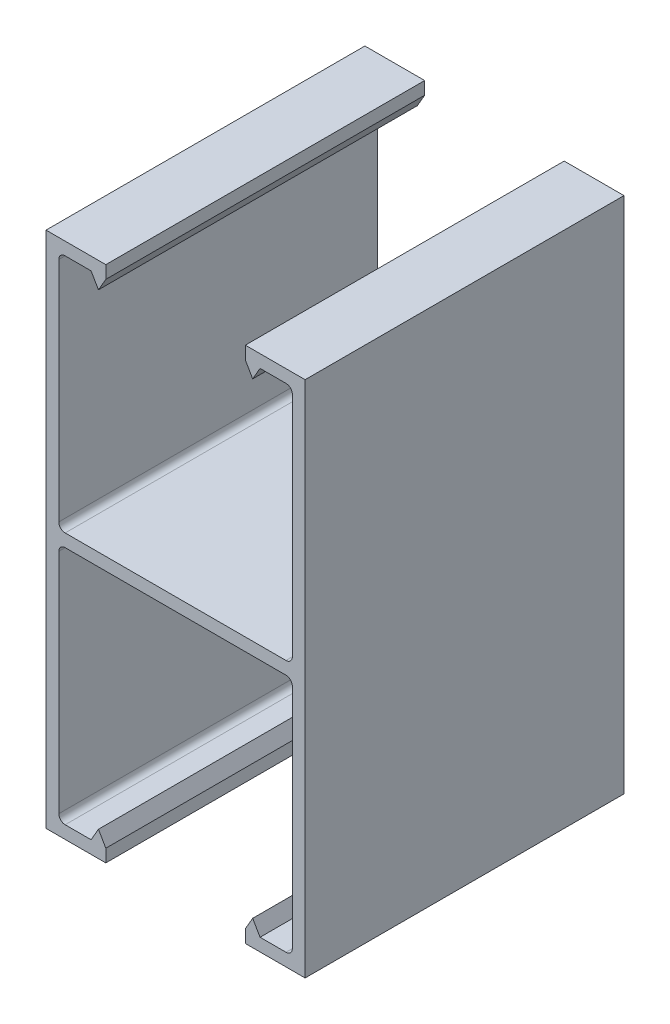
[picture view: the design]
ISO-10303-21;
HEADER;
FILE_DESCRIPTION(('STEP AP214'),'2;1');
FILE_NAME('part.step','',(''),(''),'','','');
FILE_SCHEMA(('AUTOMOTIVE_DESIGN { 1 0 10303 214 1 1 1 1 }'));
ENDSEC;
DATA;
#1=APPLICATION_CONTEXT('core data for automotive mechanical design processes');
#2=APPLICATION_PROTOCOL_DEFINITION('international standard','automotive_design',2000,#1);
#3=PRODUCT_CONTEXT('',#1,'mechanical');
#4=PRODUCT('Part','Part','',(#3));
#5=PRODUCT_RELATED_PRODUCT_CATEGORY('part','',(#4));
#6=PRODUCT_DEFINITION_FORMATION('','',#4);
#7=PRODUCT_DEFINITION_CONTEXT('part definition',#1,'design');
#8=PRODUCT_DEFINITION('design','',#6,#7);
#9=PRODUCT_DEFINITION_SHAPE('','',#8);
#10=(LENGTH_UNIT() NAMED_UNIT(*) SI_UNIT(.MILLI.,.METRE.));
#11=(NAMED_UNIT(*) PLANE_ANGLE_UNIT() SI_UNIT($,.RADIAN.));
#12=(NAMED_UNIT(*) SI_UNIT($,.STERADIAN.) SOLID_ANGLE_UNIT());
#13=UNCERTAINTY_MEASURE_WITH_UNIT(LENGTH_MEASURE(1.E-05),#10,'distance_accuracy_value','');
#14=(GEOMETRIC_REPRESENTATION_CONTEXT(3) GLOBAL_UNCERTAINTY_ASSIGNED_CONTEXT((#13)) GLOBAL_UNIT_ASSIGNED_CONTEXT((#10,
#11,#12)) REPRESENTATION_CONTEXT('',''));
#15=CARTESIAN_POINT('',(0.,0.,0.));
#16=DIRECTION('',(0.,0.,1.));
#17=DIRECTION('',(1.,0.,0.));
#18=AXIS2_PLACEMENT_3D('',#15,#16,#17);
#19=CARTESIAN_POINT('',(-8.79475,1.016,12.7));
#20=DIRECTION('',(0.,0.,-1.));
#21=DIRECTION('',(-1.,0.,0.));
#22=AXIS2_PLACEMENT_3D('',#19,#20,#21);
#23=CYLINDRICAL_SURFACE('',#22,0.508);
#24=CARTESIAN_POINT('',(-8.79475,1.016,-12.7));
#25=DIRECTION('',(0.,0.,-1.));
#26=DIRECTION('',(1.,0.,0.));
#27=AXIS2_PLACEMENT_3D('',#24,#25,#26);
#28=CIRCLE('',#27,0.508);
#29=CARTESIAN_POINT('',(-8.79475,0.508000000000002,-12.7));
#30=VERTEX_POINT('',#29);
#31=CARTESIAN_POINT('',(-9.30274999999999,1.016,-12.7));
#32=VERTEX_POINT('',#31);
#33=EDGE_CURVE('E296',#30,#32,#28,.T.);
#34=ORIENTED_EDGE('',*,*,#33,.T.);
#35=DIRECTION('',(0.,0.,-1.));
#36=VECTOR('',#35,1.);
#37=CARTESIAN_POINT('',(-9.30274999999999,1.016,12.7));
#38=LINE('',#37,#36);
#39=CARTESIAN_POINT('',(-9.30274999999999,1.016,12.7));
#40=VERTEX_POINT('',#39);
#41=EDGE_CURVE('E11',#40,#32,#38,.T.);
#42=ORIENTED_EDGE('',*,*,#41,.F.);
#43=CARTESIAN_POINT('',(-8.79475,1.016,12.7));
#44=DIRECTION('',(0.,0.,-1.));
#45=DIRECTION('',(1.,0.,0.));
#46=AXIS2_PLACEMENT_3D('',#43,#44,#45);
#47=CIRCLE('',#46,0.508);
#48=CARTESIAN_POINT('',(-8.79475,0.508000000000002,12.7));
#49=VERTEX_POINT('',#48);
#50=EDGE_CURVE('E366',#49,#40,#47,.T.);
#51=ORIENTED_EDGE('',*,*,#50,.F.);
#52=DIRECTION('',(0.,0.,-1.));
#53=VECTOR('',#52,1.);
#54=CARTESIAN_POINT('',(-8.79475,0.508000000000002,12.7));
#55=LINE('',#54,#53);
#56=EDGE_CURVE('E292',#49,#30,#55,.T.);
#57=ORIENTED_EDGE('',*,*,#56,.T.);
#58=EDGE_LOOP('',(#34,#42,#51,#57));
#59=FACE_BOUND('',#58,.T.);
#60=ADVANCED_FACE('F32',(#59),#23,.F.);
#61=CARTESIAN_POINT('',(-9.30275,19.1135,12.7));
#62=DIRECTION('',(-1.,0.,0.));
#63=DIRECTION('',(0.,-1.,0.));
#64=AXIS2_PLACEMENT_3D('',#61,#62,#63);
#65=PLANE('',#64);
#66=DIRECTION('',(0.,1.,0.));
#67=VECTOR('',#66,1.);
#68=CARTESIAN_POINT('',(-9.30275,19.1135,-12.7));
#69=LINE('',#68,#67);
#70=CARTESIAN_POINT('',(-9.30275,19.1135,-12.7));
#71=VERTEX_POINT('',#70);
#72=EDGE_CURVE('E299',#32,#71,#69,.T.);
#73=ORIENTED_EDGE('',*,*,#72,.T.);
#74=DIRECTION('',(0.,0.,-1.));
#75=VECTOR('',#74,1.);
#76=CARTESIAN_POINT('',(-9.30275,19.1135,12.7));
#77=LINE('',#76,#75);
#78=CARTESIAN_POINT('',(-9.30275,19.1135,12.7));
#79=VERTEX_POINT('',#78);
#80=EDGE_CURVE('E40',#79,#71,#77,.T.);
#81=ORIENTED_EDGE('',*,*,#80,.F.);
#82=DIRECTION('',(0.,1.,0.));
#83=VECTOR('',#82,1.);
#84=CARTESIAN_POINT('',(-9.30275,19.1135,12.7));
#85=LINE('',#84,#83);
#86=EDGE_CURVE('E175',#40,#79,#85,.T.);
#87=ORIENTED_EDGE('',*,*,#86,.F.);
#88=ORIENTED_EDGE('',*,*,#41,.T.);
#89=EDGE_LOOP('',(#73,#81,#87,#88));
#90=FACE_BOUND('',#89,.T.);
#91=ADVANCED_FACE('F564',(#90),#65,.F.);
#92=CARTESIAN_POINT('',(-8.79475,19.1135,12.7));
#93=DIRECTION('',(0.,0.,-1.));
#94=DIRECTION('',(-1.,0.,0.));
#95=AXIS2_PLACEMENT_3D('',#92,#93,#94);
#96=CYLINDRICAL_SURFACE('',#95,0.508000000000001);
#97=CARTESIAN_POINT('',(-8.79475,19.1135,-12.7));
#98=DIRECTION('',(0.,0.,-1.));
#99=DIRECTION('',(1.,0.,0.));
#100=AXIS2_PLACEMENT_3D('',#97,#98,#99);
#101=CIRCLE('',#100,0.508000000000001);
#102=CARTESIAN_POINT('',(-8.79475,19.6215,-12.7));
#103=VERTEX_POINT('',#102);
#104=EDGE_CURVE('E301',#71,#103,#101,.T.);
#105=ORIENTED_EDGE('',*,*,#104,.T.);
#106=DIRECTION('',(0.,0.,-1.));
#107=VECTOR('',#106,1.);
#108=CARTESIAN_POINT('',(-8.79475,19.6215,12.7));
#109=LINE('',#108,#107);
#110=CARTESIAN_POINT('',(-8.79475,19.6215,12.7));
#111=VERTEX_POINT('',#110);
#112=EDGE_CURVE('E457',#111,#103,#109,.T.);
#113=ORIENTED_EDGE('',*,*,#112,.F.);
#114=CARTESIAN_POINT('',(-8.79475,19.1135,12.7));
#115=DIRECTION('',(0.,0.,-1.));
#116=DIRECTION('',(1.,0.,0.));
#117=AXIS2_PLACEMENT_3D('',#114,#115,#116);
#118=CIRCLE('',#117,0.508000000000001);
#119=EDGE_CURVE('E465',#79,#111,#118,.T.);
#120=ORIENTED_EDGE('',*,*,#119,.F.);
#121=ORIENTED_EDGE('',*,*,#80,.T.);
#122=EDGE_LOOP('',(#105,#113,#120,#121));
#123=FACE_BOUND('',#122,.T.);
#124=ADVANCED_FACE('F463',(#123),#96,.F.);
#125=CARTESIAN_POINT('',(-6.72942574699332,19.6215,12.7));
#126=DIRECTION('',(0.,1.,0.));
#127=DIRECTION('',(-1.,0.,0.));
#128=AXIS2_PLACEMENT_3D('',#125,#126,#127);
#129=PLANE('',#128);
#130=DIRECTION('',(1.,0.,0.));
#131=VECTOR('',#130,1.);
#132=CARTESIAN_POINT('',(-6.72942574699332,19.6215,-12.7));
#133=LINE('',#132,#131);
#134=CARTESIAN_POINT('',(-6.72942574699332,19.6215,-12.7));
#135=VERTEX_POINT('',#134);
#136=EDGE_CURVE('E303',#103,#135,#133,.T.);
#137=ORIENTED_EDGE('',*,*,#136,.T.);
#138=DIRECTION('',(0.,0.,-1.));
#139=VECTOR('',#138,1.);
#140=CARTESIAN_POINT('',(-6.72942574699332,19.6215,12.7));
#141=LINE('',#140,#139);
#142=CARTESIAN_POINT('',(-6.72942574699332,19.6215,12.7));
#143=VERTEX_POINT('',#142);
#144=EDGE_CURVE('E454',#143,#135,#141,.T.);
#145=ORIENTED_EDGE('',*,*,#144,.F.);
#146=DIRECTION('',(1.,0.,0.));
#147=VECTOR('',#146,1.);
#148=CARTESIAN_POINT('',(-6.72942574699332,19.6215,12.7));
#149=LINE('',#148,#147);
#150=EDGE_CURVE('E483',#111,#143,#149,.T.);
#151=ORIENTED_EDGE('',*,*,#150,.F.);
#152=ORIENTED_EDGE('',*,*,#112,.T.);
#153=EDGE_LOOP('',(#137,#145,#151,#152));
#154=FACE_BOUND('',#153,.T.);
#155=ADVANCED_FACE('F474',(#154),#129,.F.);
#156=CARTESIAN_POINT('',(-6.72942574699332,19.6215,12.7));
#157=DIRECTION('',(0.866025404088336,0.499999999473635,0.));
#158=DIRECTION('',(-0.499999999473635,0.866025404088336,0.));
#159=AXIS2_PLACEMENT_3D('',#156,#157,#158);
#160=PLANE('',#159);
#161=DIRECTION('',(0.499999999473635,-0.866025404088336,0.));
#162=VECTOR('',#161,1.);
#163=CARTESIAN_POINT('',(-6.72942574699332,19.6215,-12.7));
#164=LINE('',#163,#162);
#165=CARTESIAN_POINT('',(-6.14283787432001,18.6055,-12.7));
#166=VERTEX_POINT('',#165);
#167=EDGE_CURVE('E305',#135,#166,#164,.T.);
#168=ORIENTED_EDGE('',*,*,#167,.T.);
#169=DIRECTION('',(0.,0.,-1.));
#170=VECTOR('',#169,1.);
#171=CARTESIAN_POINT('',(-6.14283787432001,18.6055,12.7));
#172=LINE('',#171,#170);
#173=CARTESIAN_POINT('',(-6.14283787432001,18.6055,12.7));
#174=VERTEX_POINT('',#173);
#175=EDGE_CURVE('E451',#174,#166,#172,.T.);
#176=ORIENTED_EDGE('',*,*,#175,.F.);
#177=DIRECTION('',(0.499999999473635,-0.866025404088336,0.));
#178=VECTOR('',#177,1.);
#179=CARTESIAN_POINT('',(-6.72942574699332,19.6215,12.7));
#180=LINE('',#179,#178);
#181=EDGE_CURVE('E480',#143,#174,#180,.T.);
#182=ORIENTED_EDGE('',*,*,#181,.F.);
#183=ORIENTED_EDGE('',*,*,#144,.T.);
#184=EDGE_LOOP('',(#168,#176,#182,#183));
#185=FACE_BOUND('',#184,.T.);
#186=ADVANCED_FACE('F478',(#185),#160,.F.);
#187=CARTESIAN_POINT('',(-6.14283787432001,18.6055,12.7));
#188=DIRECTION('',(-0.866025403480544,0.500000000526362,0.));
#189=DIRECTION('',(-0.500000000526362,-0.866025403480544,0.));
#190=AXIS2_PLACEMENT_3D('',#187,#188,#189);
#191=PLANE('',#190);
#192=DIRECTION('',(0.500000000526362,0.866025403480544,0.));
#193=VECTOR('',#192,1.);
#194=CARTESIAN_POINT('',(-6.14283787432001,18.6055,-12.7));
#195=LINE('',#194,#193);
#196=CARTESIAN_POINT('',(-5.55625,19.6215,-12.7));
#197=VERTEX_POINT('',#196);
#198=EDGE_CURVE('E307',#166,#197,#195,.T.);
#199=ORIENTED_EDGE('',*,*,#198,.T.);
#200=DIRECTION('',(0.,0.,-1.));
#201=VECTOR('',#200,1.);
#202=CARTESIAN_POINT('',(-5.55625,19.6215,12.7));
#203=LINE('',#202,#201);
#204=CARTESIAN_POINT('',(-5.55625,19.6215,12.7));
#205=VERTEX_POINT('',#204);
#206=EDGE_CURVE('E448',#205,#197,#203,.T.);
#207=ORIENTED_EDGE('',*,*,#206,.F.);
#208=DIRECTION('',(0.500000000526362,0.866025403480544,0.));
#209=VECTOR('',#208,1.);
#210=CARTESIAN_POINT('',(-6.14283787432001,18.6055,12.7));
#211=LINE('',#210,#209);
#212=EDGE_CURVE('E482',#174,#205,#211,.T.);
#213=ORIENTED_EDGE('',*,*,#212,.F.);
#214=ORIENTED_EDGE('',*,*,#175,.T.);
#215=EDGE_LOOP('',(#199,#207,#213,#214));
#216=FACE_BOUND('',#215,.T.);
#217=ADVANCED_FACE('F577',(#216),#191,.F.);
#218=CARTESIAN_POINT('',(-5.55625,19.6215,12.7));
#219=DIRECTION('',(-1.,0.,0.));
#220=DIRECTION('',(0.,0.,1.));
#221=AXIS2_PLACEMENT_3D('',#218,#219,#220);
#222=PLANE('',#221);
#223=DIRECTION('',(0.,1.,0.));
#224=VECTOR('',#223,1.);
#225=CARTESIAN_POINT('',(-5.55625,19.6215,-12.7));
#226=LINE('',#225,#224);
#227=CARTESIAN_POINT('',(-5.55625,20.6375,-12.7));
#228=VERTEX_POINT('',#227);
#229=EDGE_CURVE('E309',#197,#228,#226,.T.);
#230=ORIENTED_EDGE('',*,*,#229,.T.);
#231=DIRECTION('',(0.,0.,-1.));
#232=VECTOR('',#231,1.);
#233=CARTESIAN_POINT('',(-5.55625,20.6375,12.7));
#234=LINE('',#233,#232);
#235=CARTESIAN_POINT('',(-5.55625,20.6375,12.7));
#236=VERTEX_POINT('',#235);
#237=EDGE_CURVE('E445',#236,#228,#234,.T.);
#238=ORIENTED_EDGE('',*,*,#237,.F.);
#239=DIRECTION('',(0.,1.,0.));
#240=VECTOR('',#239,1.);
#241=CARTESIAN_POINT('',(-5.55625,19.6215,12.7));
#242=LINE('',#241,#240);
#243=EDGE_CURVE('E485',#205,#236,#242,.T.);
#244=ORIENTED_EDGE('',*,*,#243,.F.);
#245=ORIENTED_EDGE('',*,*,#206,.T.);
#246=EDGE_LOOP('',(#230,#238,#244,#245));
#247=FACE_BOUND('',#246,.T.);
#248=ADVANCED_FACE('F580',(#247),#222,.F.);
#249=CARTESIAN_POINT('',(-5.55625,20.6375,12.7));
#250=DIRECTION('',(0.,-1.,0.));
#251=DIRECTION('',(0.,0.,-1.));
#252=AXIS2_PLACEMENT_3D('',#249,#250,#251);
#253=PLANE('',#252);
#254=DIRECTION('',(-1.,0.,0.));
#255=VECTOR('',#254,1.);
#256=CARTESIAN_POINT('',(-5.55625,20.6375,-12.7));
#257=LINE('',#256,#255);
#258=CARTESIAN_POINT('',(-10.31875,20.6375,-12.7));
#259=VERTEX_POINT('',#258);
#260=EDGE_CURVE('E311',#228,#259,#257,.T.);
#261=ORIENTED_EDGE('',*,*,#260,.T.);
#262=DIRECTION('',(0.,0.,-1.));
#263=VECTOR('',#262,1.);
#264=CARTESIAN_POINT('',(-10.31875,20.6375,12.7));
#265=LINE('',#264,#263);
#266=CARTESIAN_POINT('',(-10.31875,20.6375,12.7));
#267=VERTEX_POINT('',#266);
#268=EDGE_CURVE('E442',#267,#259,#265,.T.);
#269=ORIENTED_EDGE('',*,*,#268,.F.);
#270=DIRECTION('',(-1.,0.,0.));
#271=VECTOR('',#270,1.);
#272=CARTESIAN_POINT('',(-5.55625,20.6375,12.7));
#273=LINE('',#272,#271);
#274=EDGE_CURVE('E491',#236,#267,#273,.T.);
#275=ORIENTED_EDGE('',*,*,#274,.F.);
#276=ORIENTED_EDGE('',*,*,#237,.T.);
#277=EDGE_LOOP('',(#261,#269,#275,#276));
#278=FACE_BOUND('',#277,.T.);
#279=ADVANCED_FACE('F584',(#278),#253,.F.);
#280=CARTESIAN_POINT('',(-10.31875,20.6375,12.7));
#281=DIRECTION('',(1.,0.,0.));
#282=DIRECTION('',(0.,1.,0.));
#283=AXIS2_PLACEMENT_3D('',#280,#281,#282);
#284=PLANE('',#283);
#285=DIRECTION('',(0.,-1.,0.));
#286=VECTOR('',#285,1.);
#287=CARTESIAN_POINT('',(-10.31875,20.6375,-12.7));
#288=LINE('',#287,#286);
#289=CARTESIAN_POINT('',(-10.31875,-20.6375,-12.7));
#290=VERTEX_POINT('',#289);
#291=EDGE_CURVE('E313',#259,#290,#288,.T.);
#292=ORIENTED_EDGE('',*,*,#291,.T.);
#293=DIRECTION('',(0.,0.,-1.));
#294=VECTOR('',#293,1.);
#295=CARTESIAN_POINT('',(-10.31875,-20.6375,12.7));
#296=LINE('',#295,#294);
#297=CARTESIAN_POINT('',(-10.31875,-20.6375,12.7));
#298=VERTEX_POINT('',#297);
#299=EDGE_CURVE('E439',#298,#290,#296,.T.);
#300=ORIENTED_EDGE('',*,*,#299,.F.);
#301=DIRECTION('',(0.,-1.,0.));
#302=VECTOR('',#301,1.);
#303=CARTESIAN_POINT('',(-10.31875,20.6375,12.7));
#304=LINE('',#303,#302);
#305=EDGE_CURVE('E493',#267,#298,#304,.T.);
#306=ORIENTED_EDGE('',*,*,#305,.F.);
#307=ORIENTED_EDGE('',*,*,#268,.T.);
#308=EDGE_LOOP('',(#292,#300,#306,#307));
#309=FACE_BOUND('',#308,.T.);
#310=ADVANCED_FACE('F588',(#309),#284,.F.);
#311=CARTESIAN_POINT('',(-5.55625,-20.6375,12.7));
#312=DIRECTION('',(0.,1.,0.));
#313=DIRECTION('',(0.,0.,1.));
#314=AXIS2_PLACEMENT_3D('',#311,#312,#313);
#315=PLANE('',#314);
#316=DIRECTION('',(1.,0.,0.));
#317=VECTOR('',#316,1.);
#318=CARTESIAN_POINT('',(-5.55625,-20.6375,-12.7));
#319=LINE('',#318,#317);
#320=CARTESIAN_POINT('',(-5.55625,-20.6375,-12.7));
#321=VERTEX_POINT('',#320);
#322=EDGE_CURVE('E315',#290,#321,#319,.T.);
#323=ORIENTED_EDGE('',*,*,#322,.T.);
#324=DIRECTION('',(0.,0.,-1.));
#325=VECTOR('',#324,1.);
#326=CARTESIAN_POINT('',(-5.55625,-20.6375,12.7));
#327=LINE('',#326,#325);
#328=CARTESIAN_POINT('',(-5.55625,-20.6375,12.7));
#329=VERTEX_POINT('',#328);
#330=EDGE_CURVE('E436',#329,#321,#327,.T.);
#331=ORIENTED_EDGE('',*,*,#330,.F.);
#332=DIRECTION('',(1.,0.,0.));
#333=VECTOR('',#332,1.);
#334=CARTESIAN_POINT('',(-5.55625,-20.6375,12.7));
#335=LINE('',#334,#333);
#336=EDGE_CURVE('E495',#298,#329,#335,.T.);
#337=ORIENTED_EDGE('',*,*,#336,.F.);
#338=ORIENTED_EDGE('',*,*,#299,.T.);
#339=EDGE_LOOP('',(#323,#331,#337,#338));
#340=FACE_BOUND('',#339,.T.);
#341=ADVANCED_FACE('F592',(#340),#315,.F.);
#342=CARTESIAN_POINT('',(-5.55625,-19.6215,12.7));
#343=DIRECTION('',(-1.,0.,0.));
#344=DIRECTION('',(0.,-1.,0.));
#345=AXIS2_PLACEMENT_3D('',#342,#343,#344);
#346=PLANE('',#345);
#347=DIRECTION('',(0.,1.,0.));
#348=VECTOR('',#347,1.);
#349=CARTESIAN_POINT('',(-5.55625,-19.6215,-12.7));
#350=LINE('',#349,#348);
#351=CARTESIAN_POINT('',(-5.55625,-19.6215,-12.7));
#352=VERTEX_POINT('',#351);
#353=EDGE_CURVE('E317',#321,#352,#350,.T.);
#354=ORIENTED_EDGE('',*,*,#353,.T.);
#355=DIRECTION('',(0.,0.,-1.));
#356=VECTOR('',#355,1.);
#357=CARTESIAN_POINT('',(-5.55625,-19.6215,12.7));
#358=LINE('',#357,#356);
#359=CARTESIAN_POINT('',(-5.55625,-19.6215,12.7));
#360=VERTEX_POINT('',#359);
#361=EDGE_CURVE('E433',#360,#352,#358,.T.);
#362=ORIENTED_EDGE('',*,*,#361,.F.);
#363=DIRECTION('',(0.,1.,0.));
#364=VECTOR('',#363,1.);
#365=CARTESIAN_POINT('',(-5.55625,-19.6215,12.7));
#366=LINE('',#365,#364);
#367=EDGE_CURVE('E497',#329,#360,#366,.T.);
#368=ORIENTED_EDGE('',*,*,#367,.F.);
#369=ORIENTED_EDGE('',*,*,#330,.T.);
#370=EDGE_LOOP('',(#354,#362,#368,#369));
#371=FACE_BOUND('',#370,.T.);
#372=ADVANCED_FACE('F596',(#371),#346,.F.);
#373=CARTESIAN_POINT('',(-6.14283787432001,-18.6055,12.7));
#374=DIRECTION('',(-0.866025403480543,-0.500000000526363,0.));
#375=DIRECTION('',(0.500000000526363,-0.866025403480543,0.));
#376=AXIS2_PLACEMENT_3D('',#373,#374,#375);
#377=PLANE('',#376);
#378=DIRECTION('',(-0.500000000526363,0.866025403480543,0.));
#379=VECTOR('',#378,1.);
#380=CARTESIAN_POINT('',(-6.14283787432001,-18.6055,-12.7));
#381=LINE('',#380,#379);
#382=CARTESIAN_POINT('',(-6.14283787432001,-18.6055,-12.7));
#383=VERTEX_POINT('',#382);
#384=EDGE_CURVE('E319',#352,#383,#381,.T.);
#385=ORIENTED_EDGE('',*,*,#384,.T.);
#386=DIRECTION('',(0.,0.,-1.));
#387=VECTOR('',#386,1.);
#388=CARTESIAN_POINT('',(-6.14283787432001,-18.6055,12.7));
#389=LINE('',#388,#387);
#390=CARTESIAN_POINT('',(-6.14283787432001,-18.6055,12.7));
#391=VERTEX_POINT('',#390);
#392=EDGE_CURVE('E430',#391,#383,#389,.T.);
#393=ORIENTED_EDGE('',*,*,#392,.F.);
#394=DIRECTION('',(-0.500000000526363,0.866025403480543,0.));
#395=VECTOR('',#394,1.);
#396=CARTESIAN_POINT('',(-6.14283787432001,-18.6055,12.7));
#397=LINE('',#396,#395);
#398=EDGE_CURVE('E499',#360,#391,#397,.T.);
#399=ORIENTED_EDGE('',*,*,#398,.F.);
#400=ORIENTED_EDGE('',*,*,#361,.T.);
#401=EDGE_LOOP('',(#385,#393,#399,#400));
#402=FACE_BOUND('',#401,.T.);
#403=ADVANCED_FACE('F600',(#402),#377,.F.);
#404=CARTESIAN_POINT('',(-6.72942574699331,-19.6215,12.7));
#405=DIRECTION('',(0.866025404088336,-0.499999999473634,0.));
#406=DIRECTION('',(0.499999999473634,0.866025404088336,0.));
#407=AXIS2_PLACEMENT_3D('',#404,#405,#406);
#408=PLANE('',#407);
#409=DIRECTION('',(-0.499999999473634,-0.866025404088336,0.));
#410=VECTOR('',#409,1.);
#411=CARTESIAN_POINT('',(-6.72942574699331,-19.6215,-12.7));
#412=LINE('',#411,#410);
#413=CARTESIAN_POINT('',(-6.72942574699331,-19.6215,-12.7));
#414=VERTEX_POINT('',#413);
#415=EDGE_CURVE('E321',#383,#414,#412,.T.);
#416=ORIENTED_EDGE('',*,*,#415,.T.);
#417=DIRECTION('',(0.,0.,-1.));
#418=VECTOR('',#417,1.);
#419=CARTESIAN_POINT('',(-6.72942574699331,-19.6215,12.7));
#420=LINE('',#419,#418);
#421=CARTESIAN_POINT('',(-6.72942574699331,-19.6215,12.7));
#422=VERTEX_POINT('',#421);
#423=EDGE_CURVE('E427',#422,#414,#420,.T.);
#424=ORIENTED_EDGE('',*,*,#423,.F.);
#425=DIRECTION('',(-0.499999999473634,-0.866025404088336,0.));
#426=VECTOR('',#425,1.);
#427=CARTESIAN_POINT('',(-6.72942574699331,-19.6215,12.7));
#428=LINE('',#427,#426);
#429=EDGE_CURVE('E501',#391,#422,#428,.T.);
#430=ORIENTED_EDGE('',*,*,#429,.F.);
#431=ORIENTED_EDGE('',*,*,#392,.T.);
#432=EDGE_LOOP('',(#416,#424,#430,#431));
#433=FACE_BOUND('',#432,.T.);
#434=ADVANCED_FACE('F604',(#433),#408,.F.);
#435=CARTESIAN_POINT('',(-6.72942574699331,-19.6215,12.7));
#436=DIRECTION('',(0.,-1.,0.));
#437=DIRECTION('',(1.,0.,0.));
#438=AXIS2_PLACEMENT_3D('',#435,#436,#437);
#439=PLANE('',#438);
#440=DIRECTION('',(-1.,0.,0.));
#441=VECTOR('',#440,1.);
#442=CARTESIAN_POINT('',(-6.72942574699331,-19.6215,-12.7));
#443=LINE('',#442,#441);
#444=CARTESIAN_POINT('',(-8.79475,-19.6215,-12.7));
#445=VERTEX_POINT('',#444);
#446=EDGE_CURVE('E323',#414,#445,#443,.T.);
#447=ORIENTED_EDGE('',*,*,#446,.T.);
#448=DIRECTION('',(0.,0.,-1.));
#449=VECTOR('',#448,1.);
#450=CARTESIAN_POINT('',(-8.79475,-19.6215,12.7));
#451=LINE('',#450,#449);
#452=CARTESIAN_POINT('',(-8.79475,-19.6215,12.7));
#453=VERTEX_POINT('',#452);
#454=EDGE_CURVE('E424',#453,#445,#451,.T.);
#455=ORIENTED_EDGE('',*,*,#454,.F.);
#456=DIRECTION('',(-1.,0.,0.));
#457=VECTOR('',#456,1.);
#458=CARTESIAN_POINT('',(-6.72942574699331,-19.6215,12.7));
#459=LINE('',#458,#457);
#460=EDGE_CURVE('E503',#422,#453,#459,.T.);
#461=ORIENTED_EDGE('',*,*,#460,.F.);
#462=ORIENTED_EDGE('',*,*,#423,.T.);
#463=EDGE_LOOP('',(#447,#455,#461,#462));
#464=FACE_BOUND('',#463,.T.);
#465=ADVANCED_FACE('F608',(#464),#439,.F.);
#466=CARTESIAN_POINT('',(-8.79475,-19.1135,12.7));
#467=DIRECTION('',(0.,0.,-1.));
#468=DIRECTION('',(-1.,0.,0.));
#469=AXIS2_PLACEMENT_3D('',#466,#467,#468);
#470=CYLINDRICAL_SURFACE('',#469,0.508000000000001);
#471=CARTESIAN_POINT('',(-8.79475,-19.1135,-12.7));
#472=DIRECTION('',(0.,0.,-1.));
#473=DIRECTION('',(-1.,0.,0.));
#474=AXIS2_PLACEMENT_3D('',#471,#472,#473);
#475=CIRCLE('',#474,0.508000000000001);
#476=CARTESIAN_POINT('',(-9.30275,-19.1135,-12.7));
#477=VERTEX_POINT('',#476);
#478=EDGE_CURVE('E325',#445,#477,#475,.T.);
#479=ORIENTED_EDGE('',*,*,#478,.T.);
#480=DIRECTION('',(0.,0.,-1.));
#481=VECTOR('',#480,1.);
#482=CARTESIAN_POINT('',(-9.30275,-19.1135,12.7));
#483=LINE('',#482,#481);
#484=CARTESIAN_POINT('',(-9.30275,-19.1135,12.7));
#485=VERTEX_POINT('',#484);
#486=EDGE_CURVE('E421',#485,#477,#483,.T.);
#487=ORIENTED_EDGE('',*,*,#486,.F.);
#488=CARTESIAN_POINT('',(-8.79475,-19.1135,12.7));
#489=DIRECTION('',(0.,0.,-1.));
#490=DIRECTION('',(-1.,0.,0.));
#491=AXIS2_PLACEMENT_3D('',#488,#489,#490);
#492=CIRCLE('',#491,0.508000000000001);
#493=EDGE_CURVE('E505',#453,#485,#492,.T.);
#494=ORIENTED_EDGE('',*,*,#493,.F.);
#495=ORIENTED_EDGE('',*,*,#454,.T.);
#496=EDGE_LOOP('',(#479,#487,#494,#495));
#497=FACE_BOUND('',#496,.T.);
#498=ADVANCED_FACE('F612',(#497),#470,.F.);
#499=CARTESIAN_POINT('',(-9.30275,-19.1135,12.7));
#500=DIRECTION('',(-1.,0.,0.));
#501=DIRECTION('',(0.,-1.,0.));
#502=AXIS2_PLACEMENT_3D('',#499,#500,#501);
#503=PLANE('',#502);
#504=DIRECTION('',(0.,1.,0.));
#505=VECTOR('',#504,1.);
#506=CARTESIAN_POINT('',(-9.30275,-19.1135,-12.7));
#507=LINE('',#506,#505);
#508=CARTESIAN_POINT('',(-9.30274999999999,-1.016,-12.7));
#509=VERTEX_POINT('',#508);
#510=EDGE_CURVE('E327',#477,#509,#507,.T.);
#511=ORIENTED_EDGE('',*,*,#510,.T.);
#512=DIRECTION('',(0.,0.,-1.));
#513=VECTOR('',#512,1.);
#514=CARTESIAN_POINT('',(-9.30274999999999,-1.016,12.7));
#515=LINE('',#514,#513);
#516=CARTESIAN_POINT('',(-9.30274999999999,-1.016,12.7));
#517=VERTEX_POINT('',#516);
#518=EDGE_CURVE('E418',#517,#509,#515,.T.);
#519=ORIENTED_EDGE('',*,*,#518,.F.);
#520=DIRECTION('',(0.,1.,0.));
#521=VECTOR('',#520,1.);
#522=CARTESIAN_POINT('',(-9.30275,-19.1135,12.7));
#523=LINE('',#522,#521);
#524=EDGE_CURVE('E507',#485,#517,#523,.T.);
#525=ORIENTED_EDGE('',*,*,#524,.F.);
#526=ORIENTED_EDGE('',*,*,#486,.T.);
#527=EDGE_LOOP('',(#511,#519,#525,#526));
#528=FACE_BOUND('',#527,.T.);
#529=ADVANCED_FACE('F616',(#528),#503,.F.);
#530=CARTESIAN_POINT('',(-8.79475,-1.016,12.7));
#531=DIRECTION('',(0.,0.,-1.));
#532=DIRECTION('',(-1.,0.,0.));
#533=AXIS2_PLACEMENT_3D('',#530,#531,#532);
#534=CYLINDRICAL_SURFACE('',#533,0.508);
#535=CARTESIAN_POINT('',(-8.79475,-1.016,-12.7));
#536=DIRECTION('',(0.,0.,-1.));
#537=DIRECTION('',(-1.,0.,0.));
#538=AXIS2_PLACEMENT_3D('',#535,#536,#537);
#539=CIRCLE('',#538,0.508);
#540=CARTESIAN_POINT('',(-8.79475,-0.508000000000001,-12.7));
#541=VERTEX_POINT('',#540);
#542=EDGE_CURVE('E329',#509,#541,#539,.T.);
#543=ORIENTED_EDGE('',*,*,#542,.T.);
#544=DIRECTION('',(0.,0.,-1.));
#545=VECTOR('',#544,1.);
#546=CARTESIAN_POINT('',(-8.79475,-0.508000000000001,12.7));
#547=LINE('',#546,#545);
#548=CARTESIAN_POINT('',(-8.79475,-0.508000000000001,12.7));
#549=VERTEX_POINT('',#548);
#550=EDGE_CURVE('E415',#549,#541,#547,.T.);
#551=ORIENTED_EDGE('',*,*,#550,.F.);
#552=CARTESIAN_POINT('',(-8.79475,-1.016,12.7));
#553=DIRECTION('',(0.,0.,-1.));
#554=DIRECTION('',(-1.,0.,0.));
#555=AXIS2_PLACEMENT_3D('',#552,#553,#554);
#556=CIRCLE('',#555,0.508);
#557=EDGE_CURVE('E509',#517,#549,#556,.T.);
#558=ORIENTED_EDGE('',*,*,#557,.F.);
#559=ORIENTED_EDGE('',*,*,#518,.T.);
#560=EDGE_LOOP('',(#543,#551,#558,#559));
#561=FACE_BOUND('',#560,.T.);
#562=ADVANCED_FACE('F620',(#561),#534,.F.);
#563=CARTESIAN_POINT('',(-8.79475,-0.508000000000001,12.7));
#564=DIRECTION('',(0.,1.,0.));
#565=DIRECTION('',(-1.,0.,0.));
#566=AXIS2_PLACEMENT_3D('',#563,#564,#565);
#567=PLANE('',#566);
#568=DIRECTION('',(1.,0.,0.));
#569=VECTOR('',#568,1.);
#570=CARTESIAN_POINT('',(-8.79475,-0.508000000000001,-12.7));
#571=LINE('',#570,#569);
#572=CARTESIAN_POINT('',(8.79475,-0.508000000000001,-12.7));
#573=VERTEX_POINT('',#572);
#574=EDGE_CURVE('E331',#541,#573,#571,.T.);
#575=ORIENTED_EDGE('',*,*,#574,.T.);
#576=DIRECTION('',(0.,0.,-1.));
#577=VECTOR('',#576,1.);
#578=CARTESIAN_POINT('',(8.79475,-0.508000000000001,12.7));
#579=LINE('',#578,#577);
#580=CARTESIAN_POINT('',(8.79475,-0.508000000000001,12.7));
#581=VERTEX_POINT('',#580);
#582=EDGE_CURVE('E412',#581,#573,#579,.T.);
#583=ORIENTED_EDGE('',*,*,#582,.F.);
#584=DIRECTION('',(1.,0.,0.));
#585=VECTOR('',#584,1.);
#586=CARTESIAN_POINT('',(-8.79475,-0.508000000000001,12.7));
#587=LINE('',#586,#585);
#588=EDGE_CURVE('E511',#549,#581,#587,.T.);
#589=ORIENTED_EDGE('',*,*,#588,.F.);
#590=ORIENTED_EDGE('',*,*,#550,.T.);
#591=EDGE_LOOP('',(#575,#583,#589,#590));
#592=FACE_BOUND('',#591,.T.);
#593=ADVANCED_FACE('F624',(#592),#567,.F.);
#594=CARTESIAN_POINT('',(8.79475,-1.016,12.7));
#595=DIRECTION('',(0.,0.,-1.));
#596=DIRECTION('',(-1.,0.,0.));
#597=AXIS2_PLACEMENT_3D('',#594,#595,#596);
#598=CYLINDRICAL_SURFACE('',#597,0.507999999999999);
#599=CARTESIAN_POINT('',(8.79475,-1.016,-12.7));
#600=DIRECTION('',(0.,0.,-1.));
#601=DIRECTION('',(-1.,0.,0.));
#602=AXIS2_PLACEMENT_3D('',#599,#600,#601);
#603=CIRCLE('',#602,0.507999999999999);
#604=CARTESIAN_POINT('',(9.30275,-1.016,-12.7));
#605=VERTEX_POINT('',#604);
#606=EDGE_CURVE('E333',#573,#605,#603,.T.);
#607=ORIENTED_EDGE('',*,*,#606,.T.);
#608=DIRECTION('',(0.,0.,-1.));
#609=VECTOR('',#608,1.);
#610=CARTESIAN_POINT('',(9.30275,-1.016,12.7));
#611=LINE('',#610,#609);
#612=CARTESIAN_POINT('',(9.30275,-1.016,12.7));
#613=VERTEX_POINT('',#612);
#614=EDGE_CURVE('E409',#613,#605,#611,.T.);
#615=ORIENTED_EDGE('',*,*,#614,.F.);
#616=CARTESIAN_POINT('',(8.79475,-1.016,12.7));
#617=DIRECTION('',(0.,0.,-1.));
#618=DIRECTION('',(-1.,0.,0.));
#619=AXIS2_PLACEMENT_3D('',#616,#617,#618);
#620=CIRCLE('',#619,0.507999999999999);
#621=EDGE_CURVE('E513',#581,#613,#620,.T.);
#622=ORIENTED_EDGE('',*,*,#621,.F.);
#623=ORIENTED_EDGE('',*,*,#582,.T.);
#624=EDGE_LOOP('',(#607,#615,#622,#623));
#625=FACE_BOUND('',#624,.T.);
#626=ADVANCED_FACE('F628',(#625),#598,.F.);
#627=CARTESIAN_POINT('',(9.30275,-1.016,12.7));
#628=DIRECTION('',(1.,0.,0.));
#629=DIRECTION('',(0.,1.,0.));
#630=AXIS2_PLACEMENT_3D('',#627,#628,#629);
#631=PLANE('',#630);
#632=DIRECTION('',(0.,-1.,0.));
#633=VECTOR('',#632,1.);
#634=CARTESIAN_POINT('',(9.30275,-1.016,-12.7));
#635=LINE('',#634,#633);
#636=CARTESIAN_POINT('',(9.30275000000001,-19.1135,-12.7));
#637=VERTEX_POINT('',#636);
#638=EDGE_CURVE('E335',#605,#637,#635,.T.);
#639=ORIENTED_EDGE('',*,*,#638,.T.);
#640=DIRECTION('',(0.,0.,-1.));
#641=VECTOR('',#640,1.);
#642=CARTESIAN_POINT('',(9.30275000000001,-19.1135,12.7));
#643=LINE('',#642,#641);
#644=CARTESIAN_POINT('',(9.30275000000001,-19.1135,12.7));
#645=VERTEX_POINT('',#644);
#646=EDGE_CURVE('E406',#645,#637,#643,.T.);
#647=ORIENTED_EDGE('',*,*,#646,.F.);
#648=DIRECTION('',(0.,-1.,0.));
#649=VECTOR('',#648,1.);
#650=CARTESIAN_POINT('',(9.30275,-1.016,12.7));
#651=LINE('',#650,#649);
#652=EDGE_CURVE('E515',#613,#645,#651,.T.);
#653=ORIENTED_EDGE('',*,*,#652,.F.);
#654=ORIENTED_EDGE('',*,*,#614,.T.);
#655=EDGE_LOOP('',(#639,#647,#653,#654));
#656=FACE_BOUND('',#655,.T.);
#657=ADVANCED_FACE('F632',(#656),#631,.F.);
#658=CARTESIAN_POINT('',(8.79475000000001,-19.1135,12.7));
#659=DIRECTION('',(0.,0.,-1.));
#660=DIRECTION('',(-1.,0.,0.));
#661=AXIS2_PLACEMENT_3D('',#658,#659,#660);
#662=CYLINDRICAL_SURFACE('',#661,0.508000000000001);
#663=CARTESIAN_POINT('',(8.79475000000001,-19.1135,-12.7));
#664=DIRECTION('',(0.,0.,-1.));
#665=DIRECTION('',(-1.,0.,0.));
#666=AXIS2_PLACEMENT_3D('',#663,#664,#665);
#667=CIRCLE('',#666,0.508000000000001);
#668=CARTESIAN_POINT('',(8.79475000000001,-19.6215,-12.7));
#669=VERTEX_POINT('',#668);
#670=EDGE_CURVE('E337',#637,#669,#667,.T.);
#671=ORIENTED_EDGE('',*,*,#670,.T.);
#672=DIRECTION('',(0.,0.,-1.));
#673=VECTOR('',#672,1.);
#674=CARTESIAN_POINT('',(8.79475000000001,-19.6215,12.7));
#675=LINE('',#674,#673);
#676=CARTESIAN_POINT('',(8.79475000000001,-19.6215,12.7));
#677=VERTEX_POINT('',#676);
#678=EDGE_CURVE('E403',#677,#669,#675,.T.);
#679=ORIENTED_EDGE('',*,*,#678,.F.);
#680=CARTESIAN_POINT('',(8.79475000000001,-19.1135,12.7));
#681=DIRECTION('',(0.,0.,-1.));
#682=DIRECTION('',(-1.,0.,0.));
#683=AXIS2_PLACEMENT_3D('',#680,#681,#682);
#684=CIRCLE('',#683,0.508000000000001);
#685=EDGE_CURVE('E517',#645,#677,#684,.T.);
#686=ORIENTED_EDGE('',*,*,#685,.F.);
#687=ORIENTED_EDGE('',*,*,#646,.T.);
#688=EDGE_LOOP('',(#671,#679,#686,#687));
#689=FACE_BOUND('',#688,.T.);
#690=ADVANCED_FACE('F636',(#689),#662,.F.);
#691=CARTESIAN_POINT('',(8.79475000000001,-19.6215,12.7));
#692=DIRECTION('',(0.,-1.,0.));
#693=DIRECTION('',(1.,0.,0.));
#694=AXIS2_PLACEMENT_3D('',#691,#692,#693);
#695=PLANE('',#694);
#696=DIRECTION('',(-1.,0.,0.));
#697=VECTOR('',#696,1.);
#698=CARTESIAN_POINT('',(8.79475000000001,-19.6215,-12.7));
#699=LINE('',#698,#697);
#700=CARTESIAN_POINT('',(6.72942574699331,-19.6215,-12.7));
#701=VERTEX_POINT('',#700);
#702=EDGE_CURVE('E339',#669,#701,#699,.T.);
#703=ORIENTED_EDGE('',*,*,#702,.T.);
#704=DIRECTION('',(0.,0.,-1.));
#705=VECTOR('',#704,1.);
#706=CARTESIAN_POINT('',(6.72942574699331,-19.6215,12.7));
#707=LINE('',#706,#705);
#708=CARTESIAN_POINT('',(6.72942574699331,-19.6215,12.7));
#709=VERTEX_POINT('',#708);
#710=EDGE_CURVE('E400',#709,#701,#707,.T.);
#711=ORIENTED_EDGE('',*,*,#710,.F.);
#712=DIRECTION('',(-1.,0.,0.));
#713=VECTOR('',#712,1.);
#714=CARTESIAN_POINT('',(8.79475000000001,-19.6215,12.7));
#715=LINE('',#714,#713);
#716=EDGE_CURVE('E519',#677,#709,#715,.T.);
#717=ORIENTED_EDGE('',*,*,#716,.F.);
#718=ORIENTED_EDGE('',*,*,#678,.T.);
#719=EDGE_LOOP('',(#703,#711,#717,#718));
#720=FACE_BOUND('',#719,.T.);
#721=ADVANCED_FACE('F640',(#720),#695,.F.);
#722=CARTESIAN_POINT('',(6.72942574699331,-19.6215,12.7));
#723=DIRECTION('',(-0.866025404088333,-0.499999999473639,0.));
#724=DIRECTION('',(0.499999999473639,-0.866025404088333,0.));
#725=AXIS2_PLACEMENT_3D('',#722,#723,#724);
#726=PLANE('',#725);
#727=DIRECTION('',(-0.499999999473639,0.866025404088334,0.));
#728=VECTOR('',#727,1.);
#729=CARTESIAN_POINT('',(6.72942574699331,-19.6215,-12.7));
#730=LINE('',#729,#728);
#731=CARTESIAN_POINT('',(6.14283787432,-18.6055,-12.7));
#732=VERTEX_POINT('',#731);
#733=EDGE_CURVE('E341',#701,#732,#730,.T.);
#734=ORIENTED_EDGE('',*,*,#733,.T.);
#735=DIRECTION('',(0.,0.,-1.));
#736=VECTOR('',#735,1.);
#737=CARTESIAN_POINT('',(6.14283787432,-18.6055,12.7));
#738=LINE('',#737,#736);
#739=CARTESIAN_POINT('',(6.14283787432,-18.6055,12.7));
#740=VERTEX_POINT('',#739);
#741=EDGE_CURVE('E397',#740,#732,#738,.T.);
#742=ORIENTED_EDGE('',*,*,#741,.F.);
#743=DIRECTION('',(-0.499999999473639,0.866025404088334,0.));
#744=VECTOR('',#743,1.);
#745=CARTESIAN_POINT('',(6.72942574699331,-19.6215,12.7));
#746=LINE('',#745,#744);
#747=EDGE_CURVE('E521',#709,#740,#746,.T.);
#748=ORIENTED_EDGE('',*,*,#747,.F.);
#749=ORIENTED_EDGE('',*,*,#710,.T.);
#750=EDGE_LOOP('',(#734,#742,#748,#749));
#751=FACE_BOUND('',#750,.T.);
#752=ADVANCED_FACE('F644',(#751),#726,.F.);
#753=CARTESIAN_POINT('',(6.14283787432,-18.6055,12.7));
#754=DIRECTION('',(0.866025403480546,-0.500000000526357,0.));
#755=DIRECTION('',(0.500000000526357,0.866025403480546,0.));
#756=AXIS2_PLACEMENT_3D('',#753,#754,#755);
#757=PLANE('',#756);
#758=DIRECTION('',(-0.500000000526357,-0.866025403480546,0.));
#759=VECTOR('',#758,1.);
#760=CARTESIAN_POINT('',(6.14283787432,-18.6055,-12.7));
#761=LINE('',#760,#759);
#762=CARTESIAN_POINT('',(5.55625,-19.6215,-12.7));
#763=VERTEX_POINT('',#762);
#764=EDGE_CURVE('E343',#732,#763,#761,.T.);
#765=ORIENTED_EDGE('',*,*,#764,.T.);
#766=DIRECTION('',(0.,0.,-1.));
#767=VECTOR('',#766,1.);
#768=CARTESIAN_POINT('',(5.55625,-19.6215,12.7));
#769=LINE('',#768,#767);
#770=CARTESIAN_POINT('',(5.55625,-19.6215,12.7));
#771=VERTEX_POINT('',#770);
#772=EDGE_CURVE('E394',#771,#763,#769,.T.);
#773=ORIENTED_EDGE('',*,*,#772,.F.);
#774=DIRECTION('',(-0.500000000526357,-0.866025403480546,0.));
#775=VECTOR('',#774,1.);
#776=CARTESIAN_POINT('',(6.14283787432,-18.6055,12.7));
#777=LINE('',#776,#775);
#778=EDGE_CURVE('E523',#740,#771,#777,.T.);
#779=ORIENTED_EDGE('',*,*,#778,.F.);
#780=ORIENTED_EDGE('',*,*,#741,.T.);
#781=EDGE_LOOP('',(#765,#773,#779,#780));
#782=FACE_BOUND('',#781,.T.);
#783=ADVANCED_FACE('F648',(#782),#757,.F.);
#784=CARTESIAN_POINT('',(5.55625,-19.6215,12.7));
#785=DIRECTION('',(1.,0.,0.));
#786=DIRECTION('',(0.,0.,-1.));
#787=AXIS2_PLACEMENT_3D('',#784,#785,#786);
#788=PLANE('',#787);
#789=DIRECTION('',(0.,-1.,0.));
#790=VECTOR('',#789,1.);
#791=CARTESIAN_POINT('',(5.55625,-19.6215,-12.7));
#792=LINE('',#791,#790);
#793=CARTESIAN_POINT('',(5.55625,-20.6375,-12.7));
#794=VERTEX_POINT('',#793);
#795=EDGE_CURVE('E345',#763,#794,#792,.T.);
#796=ORIENTED_EDGE('',*,*,#795,.T.);
#797=DIRECTION('',(0.,0.,-1.));
#798=VECTOR('',#797,1.);
#799=CARTESIAN_POINT('',(5.55625,-20.6375,12.7));
#800=LINE('',#799,#798);
#801=CARTESIAN_POINT('',(5.55625,-20.6375,12.7));
#802=VERTEX_POINT('',#801);
#803=EDGE_CURVE('E391',#802,#794,#800,.T.);
#804=ORIENTED_EDGE('',*,*,#803,.F.);
#805=DIRECTION('',(0.,-1.,0.));
#806=VECTOR('',#805,1.);
#807=CARTESIAN_POINT('',(5.55625,-19.6215,12.7));
#808=LINE('',#807,#806);
#809=EDGE_CURVE('E525',#771,#802,#808,.T.);
#810=ORIENTED_EDGE('',*,*,#809,.F.);
#811=ORIENTED_EDGE('',*,*,#772,.T.);
#812=EDGE_LOOP('',(#796,#804,#810,#811));
#813=FACE_BOUND('',#812,.T.);
#814=ADVANCED_FACE('F652',(#813),#788,.F.);
#815=CARTESIAN_POINT('',(10.31875,-20.6375,12.7));
#816=DIRECTION('',(0.,1.,0.));
#817=DIRECTION('',(0.,0.,1.));
#818=AXIS2_PLACEMENT_3D('',#815,#816,#817);
#819=PLANE('',#818);
#820=DIRECTION('',(1.,0.,0.));
#821=VECTOR('',#820,1.);
#822=CARTESIAN_POINT('',(10.31875,-20.6375,-12.7));
#823=LINE('',#822,#821);
#824=CARTESIAN_POINT('',(10.31875,-20.6375,-12.7));
#825=VERTEX_POINT('',#824);
#826=EDGE_CURVE('E347',#794,#825,#823,.T.);
#827=ORIENTED_EDGE('',*,*,#826,.T.);
#828=DIRECTION('',(0.,0.,-1.));
#829=VECTOR('',#828,1.);
#830=CARTESIAN_POINT('',(10.31875,-20.6375,12.7));
#831=LINE('',#830,#829);
#832=CARTESIAN_POINT('',(10.31875,-20.6375,12.7));
#833=VERTEX_POINT('',#832);
#834=EDGE_CURVE('E388',#833,#825,#831,.T.);
#835=ORIENTED_EDGE('',*,*,#834,.F.);
#836=DIRECTION('',(1.,0.,0.));
#837=VECTOR('',#836,1.);
#838=CARTESIAN_POINT('',(10.31875,-20.6375,12.7));
#839=LINE('',#838,#837);
#840=EDGE_CURVE('E527',#802,#833,#839,.T.);
#841=ORIENTED_EDGE('',*,*,#840,.F.);
#842=ORIENTED_EDGE('',*,*,#803,.T.);
#843=EDGE_LOOP('',(#827,#835,#841,#842));
#844=FACE_BOUND('',#843,.T.);
#845=ADVANCED_FACE('F656',(#844),#819,.F.);
#846=CARTESIAN_POINT('',(10.31875,-20.6375,12.7));
#847=DIRECTION('',(-1.,0.,0.));
#848=DIRECTION('',(0.,-1.,0.));
#849=AXIS2_PLACEMENT_3D('',#846,#847,#848);
#850=PLANE('',#849);
#851=DIRECTION('',(0.,1.,0.));
#852=VECTOR('',#851,1.);
#853=CARTESIAN_POINT('',(10.31875,-20.6375,-12.7));
#854=LINE('',#853,#852);
#855=CARTESIAN_POINT('',(10.31875,20.6375,-12.7));
#856=VERTEX_POINT('',#855);
#857=EDGE_CURVE('E349',#825,#856,#854,.T.);
#858=ORIENTED_EDGE('',*,*,#857,.T.);
#859=DIRECTION('',(0.,0.,-1.));
#860=VECTOR('',#859,1.);
#861=CARTESIAN_POINT('',(10.31875,20.6375,12.7));
#862=LINE('',#861,#860);
#863=CARTESIAN_POINT('',(10.31875,20.6375,12.7));
#864=VERTEX_POINT('',#863);
#865=EDGE_CURVE('E385',#864,#856,#862,.T.);
#866=ORIENTED_EDGE('',*,*,#865,.F.);
#867=DIRECTION('',(0.,1.,0.));
#868=VECTOR('',#867,1.);
#869=CARTESIAN_POINT('',(10.31875,-20.6375,12.7));
#870=LINE('',#869,#868);
#871=EDGE_CURVE('E529',#833,#864,#870,.T.);
#872=ORIENTED_EDGE('',*,*,#871,.F.);
#873=ORIENTED_EDGE('',*,*,#834,.T.);
#874=EDGE_LOOP('',(#858,#866,#872,#873));
#875=FACE_BOUND('',#874,.T.);
#876=ADVANCED_FACE('F660',(#875),#850,.F.);
#877=CARTESIAN_POINT('',(10.31875,20.6375,12.7));
#878=DIRECTION('',(0.,-1.,0.));
#879=DIRECTION('',(1.,0.,0.));
#880=AXIS2_PLACEMENT_3D('',#877,#878,#879);
#881=PLANE('',#880);
#882=DIRECTION('',(-1.,0.,0.));
#883=VECTOR('',#882,1.);
#884=CARTESIAN_POINT('',(10.31875,20.6375,-12.7));
#885=LINE('',#884,#883);
#886=CARTESIAN_POINT('',(5.55624999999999,20.6375,-12.7));
#887=VERTEX_POINT('',#886);
#888=EDGE_CURVE('E351',#856,#887,#885,.T.);
#889=ORIENTED_EDGE('',*,*,#888,.T.);
#890=DIRECTION('',(0.,0.,-1.));
#891=VECTOR('',#890,1.);
#892=CARTESIAN_POINT('',(5.55624999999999,20.6375,12.7));
#893=LINE('',#892,#891);
#894=CARTESIAN_POINT('',(5.55624999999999,20.6375,12.7));
#895=VERTEX_POINT('',#894);
#896=EDGE_CURVE('E382',#895,#887,#893,.T.);
#897=ORIENTED_EDGE('',*,*,#896,.F.);
#898=DIRECTION('',(-1.,0.,0.));
#899=VECTOR('',#898,1.);
#900=CARTESIAN_POINT('',(10.31875,20.6375,12.7));
#901=LINE('',#900,#899);
#902=EDGE_CURVE('E531',#864,#895,#901,.T.);
#903=ORIENTED_EDGE('',*,*,#902,.F.);
#904=ORIENTED_EDGE('',*,*,#865,.T.);
#905=EDGE_LOOP('',(#889,#897,#903,#904));
#906=FACE_BOUND('',#905,.T.);
#907=ADVANCED_FACE('F664',(#906),#881,.F.);
#908=CARTESIAN_POINT('',(5.55624999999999,19.6215,12.7));
#909=DIRECTION('',(1.,0.,0.));
#910=DIRECTION('',(0.,1.,0.));
#911=AXIS2_PLACEMENT_3D('',#908,#909,#910);
#912=PLANE('',#911);
#913=DIRECTION('',(0.,-1.,0.));
#914=VECTOR('',#913,1.);
#915=CARTESIAN_POINT('',(5.55624999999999,19.6215,-12.7));
#916=LINE('',#915,#914);
#917=CARTESIAN_POINT('',(5.55624999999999,19.6215,-12.7));
#918=VERTEX_POINT('',#917);
#919=EDGE_CURVE('E353',#887,#918,#916,.T.);
#920=ORIENTED_EDGE('',*,*,#919,.T.);
#921=DIRECTION('',(0.,0.,-1.));
#922=VECTOR('',#921,1.);
#923=CARTESIAN_POINT('',(5.55624999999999,19.6215,12.7));
#924=LINE('',#923,#922);
#925=CARTESIAN_POINT('',(5.55624999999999,19.6215,12.7));
#926=VERTEX_POINT('',#925);
#927=EDGE_CURVE('E379',#926,#918,#924,.T.);
#928=ORIENTED_EDGE('',*,*,#927,.F.);
#929=DIRECTION('',(0.,-1.,0.));
#930=VECTOR('',#929,1.);
#931=CARTESIAN_POINT('',(5.55624999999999,19.6215,12.7));
#932=LINE('',#931,#930);
#933=EDGE_CURVE('E533',#895,#926,#932,.T.);
#934=ORIENTED_EDGE('',*,*,#933,.F.);
#935=ORIENTED_EDGE('',*,*,#896,.T.);
#936=EDGE_LOOP('',(#920,#928,#934,#935));
#937=FACE_BOUND('',#936,.T.);
#938=ADVANCED_FACE('F668',(#937),#912,.F.);
#939=CARTESIAN_POINT('',(6.14283787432,18.6055,12.7));
#940=DIRECTION('',(0.866025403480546,0.500000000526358,0.));
#941=DIRECTION('',(-0.500000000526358,0.866025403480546,0.));
#942=AXIS2_PLACEMENT_3D('',#939,#940,#941);
#943=PLANE('',#942);
#944=DIRECTION('',(0.500000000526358,-0.866025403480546,0.));
#945=VECTOR('',#944,1.);
#946=CARTESIAN_POINT('',(6.14283787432,18.6055,-12.7));
#947=LINE('',#946,#945);
#948=CARTESIAN_POINT('',(6.14283787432,18.6055,-12.7));
#949=VERTEX_POINT('',#948);
#950=EDGE_CURVE('E355',#918,#949,#947,.T.);
#951=ORIENTED_EDGE('',*,*,#950,.T.);
#952=DIRECTION('',(0.,0.,-1.));
#953=VECTOR('',#952,1.);
#954=CARTESIAN_POINT('',(6.14283787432,18.6055,12.7));
#955=LINE('',#954,#953);
#956=CARTESIAN_POINT('',(6.14283787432,18.6055,12.7));
#957=VERTEX_POINT('',#956);
#958=EDGE_CURVE('E376',#957,#949,#955,.T.);
#959=ORIENTED_EDGE('',*,*,#958,.F.);
#960=DIRECTION('',(0.500000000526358,-0.866025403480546,0.));
#961=VECTOR('',#960,1.);
#962=CARTESIAN_POINT('',(6.14283787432,18.6055,12.7));
#963=LINE('',#962,#961);
#964=EDGE_CURVE('E535',#926,#957,#963,.T.);
#965=ORIENTED_EDGE('',*,*,#964,.F.);
#966=ORIENTED_EDGE('',*,*,#927,.T.);
#967=EDGE_LOOP('',(#951,#959,#965,#966));
#968=FACE_BOUND('',#967,.T.);
#969=ADVANCED_FACE('F672',(#968),#943,.F.);
#970=CARTESIAN_POINT('',(6.7294257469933,19.6215,12.7));
#971=DIRECTION('',(-0.866025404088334,0.499999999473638,0.));
#972=DIRECTION('',(-0.499999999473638,-0.866025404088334,0.));
#973=AXIS2_PLACEMENT_3D('',#970,#971,#972);
#974=PLANE('',#973);
#975=DIRECTION('',(0.499999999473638,0.866025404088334,0.));
#976=VECTOR('',#975,1.);
#977=CARTESIAN_POINT('',(6.7294257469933,19.6215,-12.7));
#978=LINE('',#977,#976);
#979=CARTESIAN_POINT('',(6.7294257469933,19.6215,-12.7));
#980=VERTEX_POINT('',#979);
#981=EDGE_CURVE('E357',#949,#980,#978,.T.);
#982=ORIENTED_EDGE('',*,*,#981,.T.);
#983=DIRECTION('',(0.,0.,-1.));
#984=VECTOR('',#983,1.);
#985=CARTESIAN_POINT('',(6.7294257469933,19.6215,12.7));
#986=LINE('',#985,#984);
#987=CARTESIAN_POINT('',(6.7294257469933,19.6215,12.7));
#988=VERTEX_POINT('',#987);
#989=EDGE_CURVE('E373',#988,#980,#986,.T.);
#990=ORIENTED_EDGE('',*,*,#989,.F.);
#991=DIRECTION('',(0.499999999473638,0.866025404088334,0.));
#992=VECTOR('',#991,1.);
#993=CARTESIAN_POINT('',(6.7294257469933,19.6215,12.7));
#994=LINE('',#993,#992);
#995=EDGE_CURVE('E537',#957,#988,#994,.T.);
#996=ORIENTED_EDGE('',*,*,#995,.F.);
#997=ORIENTED_EDGE('',*,*,#958,.T.);
#998=EDGE_LOOP('',(#982,#990,#996,#997));
#999=FACE_BOUND('',#998,.T.);
#1000=ADVANCED_FACE('F676',(#999),#974,.F.);
#1001=CARTESIAN_POINT('',(8.79475000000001,19.6215,12.7));
#1002=DIRECTION('',(0.,1.,0.));
#1003=DIRECTION('',(0.,0.,1.));
#1004=AXIS2_PLACEMENT_3D('',#1001,#1002,#1003);
#1005=PLANE('',#1004);
#1006=DIRECTION('',(1.,0.,0.));
#1007=VECTOR('',#1006,1.);
#1008=CARTESIAN_POINT('',(8.79475000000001,19.6215,-12.7));
#1009=LINE('',#1008,#1007);
#1010=CARTESIAN_POINT('',(8.79475000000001,19.6215,-12.7));
#1011=VERTEX_POINT('',#1010);
#1012=EDGE_CURVE('E359',#980,#1011,#1009,.T.);
#1013=ORIENTED_EDGE('',*,*,#1012,.T.);
#1014=DIRECTION('',(0.,0.,-1.));
#1015=VECTOR('',#1014,1.);
#1016=CARTESIAN_POINT('',(8.79475000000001,19.6215,12.7));
#1017=LINE('',#1016,#1015);
#1018=CARTESIAN_POINT('',(8.79475000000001,19.6215,12.7));
#1019=VERTEX_POINT('',#1018);
#1020=EDGE_CURVE('E370',#1019,#1011,#1017,.T.);
#1021=ORIENTED_EDGE('',*,*,#1020,.F.);
#1022=DIRECTION('',(1.,0.,0.));
#1023=VECTOR('',#1022,1.);
#1024=CARTESIAN_POINT('',(8.79475000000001,19.6215,12.7));
#1025=LINE('',#1024,#1023);
#1026=EDGE_CURVE('E539',#988,#1019,#1025,.T.);
#1027=ORIENTED_EDGE('',*,*,#1026,.F.);
#1028=ORIENTED_EDGE('',*,*,#989,.T.);
#1029=EDGE_LOOP('',(#1013,#1021,#1027,#1028));
#1030=FACE_BOUND('',#1029,.T.);
#1031=ADVANCED_FACE('F545',(#1030),#1005,.F.);
#1032=CARTESIAN_POINT('',(8.79475000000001,19.1135,12.7));
#1033=DIRECTION('',(0.,0.,-1.));
#1034=DIRECTION('',(-1.,0.,0.));
#1035=AXIS2_PLACEMENT_3D('',#1032,#1033,#1034);
#1036=CYLINDRICAL_SURFACE('',#1035,0.508000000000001);
#1037=CARTESIAN_POINT('',(8.79475000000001,19.1135,-12.7));
#1038=DIRECTION('',(0.,0.,-1.));
#1039=DIRECTION('',(1.,0.,0.));
#1040=AXIS2_PLACEMENT_3D('',#1037,#1038,#1039);
#1041=CIRCLE('',#1040,0.508000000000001);
#1042=CARTESIAN_POINT('',(9.30275,19.1135,-12.7));
#1043=VERTEX_POINT('',#1042);
#1044=EDGE_CURVE('E361',#1011,#1043,#1041,.T.);
#1045=ORIENTED_EDGE('',*,*,#1044,.T.);
#1046=DIRECTION('',(0.,0.,-1.));
#1047=VECTOR('',#1046,1.);
#1048=CARTESIAN_POINT('',(9.30275,19.1135,12.7));
#1049=LINE('',#1048,#1047);
#1050=CARTESIAN_POINT('',(9.30275,19.1135,12.7));
#1051=VERTEX_POINT('',#1050);
#1052=EDGE_CURVE('E287',#1051,#1043,#1049,.T.);
#1053=ORIENTED_EDGE('',*,*,#1052,.F.);
#1054=CARTESIAN_POINT('',(8.79475000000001,19.1135,12.7));
#1055=DIRECTION('',(0.,0.,-1.));
#1056=DIRECTION('',(1.,0.,0.));
#1057=AXIS2_PLACEMENT_3D('',#1054,#1055,#1056);
#1058=CIRCLE('',#1057,0.508000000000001);
#1059=EDGE_CURVE('E278',#1019,#1051,#1058,.T.);
#1060=ORIENTED_EDGE('',*,*,#1059,.F.);
#1061=ORIENTED_EDGE('',*,*,#1020,.T.);
#1062=EDGE_LOOP('',(#1045,#1053,#1060,#1061));
#1063=FACE_BOUND('',#1062,.T.);
#1064=ADVANCED_FACE('F549',(#1063),#1036,.F.);
#1065=CARTESIAN_POINT('',(9.30275,1.01600000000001,12.7));
#1066=DIRECTION('',(1.,0.,0.));
#1067=DIRECTION('',(0.,1.,0.));
#1068=AXIS2_PLACEMENT_3D('',#1065,#1066,#1067);
#1069=PLANE('',#1068);
#1070=DIRECTION('',(0.,-1.,0.));
#1071=VECTOR('',#1070,1.);
#1072=CARTESIAN_POINT('',(9.30275,1.01600000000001,-12.7));
#1073=LINE('',#1072,#1071);
#1074=CARTESIAN_POINT('',(9.30275,1.01600000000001,-12.7));
#1075=VERTEX_POINT('',#1074);
#1076=EDGE_CURVE('E286',#1043,#1075,#1073,.T.);
#1077=ORIENTED_EDGE('',*,*,#1076,.T.);
#1078=DIRECTION('',(0.,0.,-1.));
#1079=VECTOR('',#1078,1.);
#1080=CARTESIAN_POINT('',(9.30275,1.01600000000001,12.7));
#1081=LINE('',#1080,#1079);
#1082=CARTESIAN_POINT('',(9.30275,1.01600000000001,12.7));
#1083=VERTEX_POINT('',#1082);
#1084=EDGE_CURVE('E283',#1083,#1075,#1081,.T.);
#1085=ORIENTED_EDGE('',*,*,#1084,.F.);
#1086=DIRECTION('',(0.,-1.,0.));
#1087=VECTOR('',#1086,1.);
#1088=CARTESIAN_POINT('',(9.30275,1.01600000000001,12.7));
#1089=LINE('',#1088,#1087);
#1090=EDGE_CURVE('E272',#1051,#1083,#1089,.T.);
#1091=ORIENTED_EDGE('',*,*,#1090,.F.);
#1092=ORIENTED_EDGE('',*,*,#1052,.T.);
#1093=EDGE_LOOP('',(#1077,#1085,#1091,#1092));
#1094=FACE_BOUND('',#1093,.T.);
#1095=ADVANCED_FACE('F284',(#1094),#1069,.F.);
#1096=CARTESIAN_POINT('',(8.79475,1.01600000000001,12.7));
#1097=DIRECTION('',(0.,0.,-1.));
#1098=DIRECTION('',(-1.,0.,0.));
#1099=AXIS2_PLACEMENT_3D('',#1096,#1097,#1098);
#1100=CYLINDRICAL_SURFACE('',#1099,0.507999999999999);
#1101=CARTESIAN_POINT('',(8.79475,1.01600000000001,-12.7));
#1102=DIRECTION('',(0.,0.,-1.));
#1103=DIRECTION('',(1.,0.,0.));
#1104=AXIS2_PLACEMENT_3D('',#1101,#1102,#1103);
#1105=CIRCLE('',#1104,0.507999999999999);
#1106=CARTESIAN_POINT('',(8.79475,0.508000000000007,-12.7));
#1107=VERTEX_POINT('',#1106);
#1108=EDGE_CURVE('E161',#1075,#1107,#1105,.T.);
#1109=ORIENTED_EDGE('',*,*,#1108,.T.);
#1110=DIRECTION('',(0.,0.,-1.));
#1111=VECTOR('',#1110,1.);
#1112=CARTESIAN_POINT('',(8.79475,0.508000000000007,12.7));
#1113=LINE('',#1112,#1111);
#1114=CARTESIAN_POINT('',(8.79475,0.508000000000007,12.7));
#1115=VERTEX_POINT('',#1114);
#1116=EDGE_CURVE('E288',#1115,#1107,#1113,.T.);
#1117=ORIENTED_EDGE('',*,*,#1116,.F.);
#1118=CARTESIAN_POINT('',(8.79475,1.01600000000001,12.7));
#1119=DIRECTION('',(0.,0.,-1.));
#1120=DIRECTION('',(1.,0.,0.));
#1121=AXIS2_PLACEMENT_3D('',#1118,#1119,#1120);
#1122=CIRCLE('',#1121,0.507999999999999);
#1123=EDGE_CURVE('E276',#1083,#1115,#1122,.T.);
#1124=ORIENTED_EDGE('',*,*,#1123,.F.);
#1125=ORIENTED_EDGE('',*,*,#1084,.T.);
#1126=EDGE_LOOP('',(#1109,#1117,#1124,#1125));
#1127=FACE_BOUND('',#1126,.T.);
#1128=ADVANCED_FACE('F290',(#1127),#1100,.F.);
#1129=CARTESIAN_POINT('',(-8.79475,0.508000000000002,12.7));
#1130=DIRECTION('',(0.,-1.,0.));
#1131=DIRECTION('',(1.,0.,0.));
#1132=AXIS2_PLACEMENT_3D('',#1129,#1130,#1131);
#1133=PLANE('',#1132);
#1134=DIRECTION('',(-1.,0.,0.));
#1135=VECTOR('',#1134,1.);
#1136=CARTESIAN_POINT('',(-8.79475,0.508000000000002,-12.7));
#1137=LINE('',#1136,#1135);
#1138=EDGE_CURVE('E167',#1107,#30,#1137,.T.);
#1139=ORIENTED_EDGE('',*,*,#1138,.T.);
#1140=ORIENTED_EDGE('',*,*,#56,.F.);
#1141=DIRECTION('',(-1.,0.,0.));
#1142=VECTOR('',#1141,1.);
#1143=CARTESIAN_POINT('',(-8.79475,0.508000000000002,12.7));
#1144=LINE('',#1143,#1142);
#1145=EDGE_CURVE('E48',#1115,#49,#1144,.T.);
#1146=ORIENTED_EDGE('',*,*,#1145,.F.);
#1147=ORIENTED_EDGE('',*,*,#1116,.T.);
#1148=EDGE_LOOP('',(#1139,#1140,#1146,#1147));
#1149=FACE_BOUND('',#1148,.T.);
#1150=ADVANCED_FACE('F553',(#1149),#1133,.F.);
#1151=CARTESIAN_POINT('',(-8.79475,1.016,12.7));
#1152=DIRECTION('',(0.,0.,1.));
#1153=DIRECTION('',(1.,0.,0.));
#1154=AXIS2_PLACEMENT_3D('',#1151,#1152,#1153);
#1155=PLANE('',#1154);
#1156=ORIENTED_EDGE('',*,*,#50,.T.);
#1157=ORIENTED_EDGE('',*,*,#86,.T.);
#1158=ORIENTED_EDGE('',*,*,#119,.T.);
#1159=ORIENTED_EDGE('',*,*,#150,.T.);
#1160=ORIENTED_EDGE('',*,*,#181,.T.);
#1161=ORIENTED_EDGE('',*,*,#212,.T.);
#1162=ORIENTED_EDGE('',*,*,#243,.T.);
#1163=ORIENTED_EDGE('',*,*,#274,.T.);
#1164=ORIENTED_EDGE('',*,*,#305,.T.);
#1165=ORIENTED_EDGE('',*,*,#336,.T.);
#1166=ORIENTED_EDGE('',*,*,#367,.T.);
#1167=ORIENTED_EDGE('',*,*,#398,.T.);
#1168=ORIENTED_EDGE('',*,*,#429,.T.);
#1169=ORIENTED_EDGE('',*,*,#460,.T.);
#1170=ORIENTED_EDGE('',*,*,#493,.T.);
#1171=ORIENTED_EDGE('',*,*,#524,.T.);
#1172=ORIENTED_EDGE('',*,*,#557,.T.);
#1173=ORIENTED_EDGE('',*,*,#588,.T.);
#1174=ORIENTED_EDGE('',*,*,#621,.T.);
#1175=ORIENTED_EDGE('',*,*,#652,.T.);
#1176=ORIENTED_EDGE('',*,*,#685,.T.);
#1177=ORIENTED_EDGE('',*,*,#716,.T.);
#1178=ORIENTED_EDGE('',*,*,#747,.T.);
#1179=ORIENTED_EDGE('',*,*,#778,.T.);
#1180=ORIENTED_EDGE('',*,*,#809,.T.);
#1181=ORIENTED_EDGE('',*,*,#840,.T.);
#1182=ORIENTED_EDGE('',*,*,#871,.T.);
#1183=ORIENTED_EDGE('',*,*,#902,.T.);
#1184=ORIENTED_EDGE('',*,*,#933,.T.);
#1185=ORIENTED_EDGE('',*,*,#964,.T.);
#1186=ORIENTED_EDGE('',*,*,#995,.T.);
#1187=ORIENTED_EDGE('',*,*,#1026,.T.);
#1188=ORIENTED_EDGE('',*,*,#1059,.T.);
#1189=ORIENTED_EDGE('',*,*,#1090,.T.);
#1190=ORIENTED_EDGE('',*,*,#1123,.T.);
#1191=ORIENTED_EDGE('',*,*,#1145,.T.);
#1192=EDGE_LOOP('',(#1156,#1157,#1158,#1159,#1160,#1161,#1162,#1163,#1164,#1165,#1166,#1167,
#1168,#1169,#1170,#1171,#1172,#1173,#1174,#1175,#1176,#1177,#1178,#1179,#1180,#1181,#1182,#1183,
#1184,#1185,#1186,#1187,#1188,#1189,#1190,#1191));
#1193=FACE_BOUND('',#1192,.T.);
#1194=ADVANCED_FACE('F274',(#1193),#1155,.T.);
#1195=CARTESIAN_POINT('',(-8.79475,1.016,-12.7));
#1196=DIRECTION('',(0.,0.,1.));
#1197=DIRECTION('',(1.,0.,0.));
#1198=AXIS2_PLACEMENT_3D('',#1195,#1196,#1197);
#1199=PLANE('',#1198);
#1200=ORIENTED_EDGE('',*,*,#33,.F.);
#1201=ORIENTED_EDGE('',*,*,#1138,.F.);
#1202=ORIENTED_EDGE('',*,*,#1108,.F.);
#1203=ORIENTED_EDGE('',*,*,#1076,.F.);
#1204=ORIENTED_EDGE('',*,*,#1044,.F.);
#1205=ORIENTED_EDGE('',*,*,#1012,.F.);
#1206=ORIENTED_EDGE('',*,*,#981,.F.);
#1207=ORIENTED_EDGE('',*,*,#950,.F.);
#1208=ORIENTED_EDGE('',*,*,#919,.F.);
#1209=ORIENTED_EDGE('',*,*,#888,.F.);
#1210=ORIENTED_EDGE('',*,*,#857,.F.);
#1211=ORIENTED_EDGE('',*,*,#826,.F.);
#1212=ORIENTED_EDGE('',*,*,#795,.F.);
#1213=ORIENTED_EDGE('',*,*,#764,.F.);
#1214=ORIENTED_EDGE('',*,*,#733,.F.);
#1215=ORIENTED_EDGE('',*,*,#702,.F.);
#1216=ORIENTED_EDGE('',*,*,#670,.F.);
#1217=ORIENTED_EDGE('',*,*,#638,.F.);
#1218=ORIENTED_EDGE('',*,*,#606,.F.);
#1219=ORIENTED_EDGE('',*,*,#574,.F.);
#1220=ORIENTED_EDGE('',*,*,#542,.F.);
#1221=ORIENTED_EDGE('',*,*,#510,.F.);
#1222=ORIENTED_EDGE('',*,*,#478,.F.);
#1223=ORIENTED_EDGE('',*,*,#446,.F.);
#1224=ORIENTED_EDGE('',*,*,#415,.F.);
#1225=ORIENTED_EDGE('',*,*,#384,.F.);
#1226=ORIENTED_EDGE('',*,*,#353,.F.);
#1227=ORIENTED_EDGE('',*,*,#322,.F.);
#1228=ORIENTED_EDGE('',*,*,#291,.F.);
#1229=ORIENTED_EDGE('',*,*,#260,.F.);
#1230=ORIENTED_EDGE('',*,*,#229,.F.);
#1231=ORIENTED_EDGE('',*,*,#198,.F.);
#1232=ORIENTED_EDGE('',*,*,#167,.F.);
#1233=ORIENTED_EDGE('',*,*,#136,.F.);
#1234=ORIENTED_EDGE('',*,*,#104,.F.);
#1235=ORIENTED_EDGE('',*,*,#72,.F.);
#1236=EDGE_LOOP('',(#1200,#1201,#1202,#1203,#1204,#1205,#1206,#1207,#1208,#1209,#1210,#1211,
#1212,#1213,#1214,#1215,#1216,#1217,#1218,#1219,#1220,#1221,#1222,#1223,#1224,#1225,#1226,#1227,
#1228,#1229,#1230,#1231,#1232,#1233,#1234,#1235));
#1237=FACE_BOUND('',#1236,.T.);
#1238=ADVANCED_FACE('F469',(#1237),#1199,.F.);
#1239=CLOSED_SHELL('',(#60,#91,#124,#155,#186,#217,#248,#279,#310,#341,#372,#403,#434,#465,#498,
#529,#562,#593,#626,#657,#690,#721,#752,#783,#814,#845,#876,#907,#938,#969,#1000,#1031,#1064,
#1095,#1128,#1150,#1194,#1238));
#1240=MANIFOLD_SOLID_BREP('B2',#1239);
#1241=ADVANCED_BREP_SHAPE_REPRESENTATION('',(#18,#1240),#14);
#1242=SHAPE_DEFINITION_REPRESENTATION(#9,#1241);
ENDSEC;
END-ISO-10303-21;
